VERSION 5.8 ;
BUSBITCHARS "[]" ;
DIVIDERCHAR "/" ;
UNITS
  DATABASE MICRONS 1000 ;
END UNITS
MANUFACTURINGGRID 0.005 ;
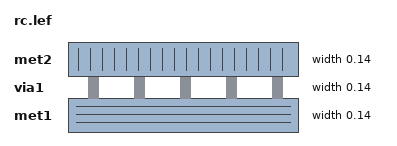
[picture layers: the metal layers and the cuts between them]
LAYER met1
  TYPE ROUTING ;
  DIRECTION HORIZONTAL ;
  WIDTH 0.14 ;
  RESISTANCE RPERSQ 0.125 ;
  CAPACITANCE CPERSQDIST 0.00007 ;
  EDGECAPACITANCE 0.00004 ;
END met1
LAYER via1
  TYPE CUT ;
  WIDTH 0.14 ;
  RESISTANCE 4.5 ;
END via1
LAYER met2
  TYPE ROUTING ;
  DIRECTION VERTICAL ;
  WIDTH 0.14 ;
  RESISTANCE RPERSQ 0.125 ;
  CAPACITANCE CPERSQDIST 0.00007 ;
END met2
END LIBRARY
